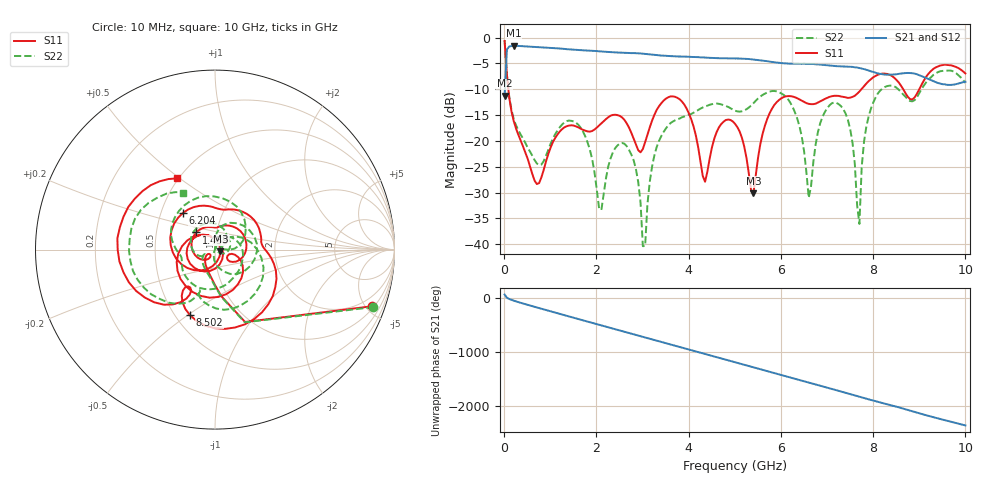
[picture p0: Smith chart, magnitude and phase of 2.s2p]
!Agilent Technologies,N5230C,MY49000813,A.09.42.22
!Agilent N5230C: A.09.42.22
!Date: Friday, August 21, 2026 19:33:07
!Correction: S11(Full 2 Port(1,2))
!S21(Full 2 Port(1,2))
!S12(Full 2 Port(1,2))
!S22(Full 2 Port(1,2))
!S2P File: Measurements: S11, S21, S12, S22:
# Hz S  dB  R 50
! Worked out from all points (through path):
!   201 points, 10 MHz to 10 GHz, reference 50 ohm
!   highest |S21| = -1.59 dB at 209.8 MHz (marker M1); lowest = -11.2 dB at 10 MHz (marker M2)
!   lowest |S11| = -30.1 dB at 5.405 GHz (marker M3), VSWR 1.06, Z = 53.1 - j0.895 ohm
!   |S11| at or under -10 dB: 91.73 MHz to 7.746 GHz (7.654 GHz wide, 195 % of centre); 8.653 GHz to 9 GHz (347.9 MHz wide, 3.94 % of centre)
!   |S22| runs from -40.4 to -0.5 dB; largest |S21 - S12| = 0.0031
!   S11 on the Smith chart (normalised r, x): 10 MHz: 1.16, -5.49; 1.459 GHz: 0.80, +0.16; 6.204 GHz: 0.65, +0.28; 8.502 GHz: 0.59, -0.51; 10 GHz: 0.49, +0.49
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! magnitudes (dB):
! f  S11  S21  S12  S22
! 10 MHz  -0.6  -11.2  -11.3  -0.5
! 209.8 MHz  -16.2  -1.6  -1.6  -15.8
! 709.3 MHz  -28.4  -1.8  -1.8  -24.4
! 1.459 GHz  -17.0  -2.3  -2.3  -16.1
! 1.708 GHz  -17.9  -2.5  -2.4  -18.2
! 2.108 GHz  -16.6  -2.7  -2.7  -33.4
! 2.707 GHz  -17.4  -3.0  -3.0  -21.7
! 3.007 GHz  -21.6  -3.1  -3.1  -40.4
! 3.357 GHz  -13.3  -3.4  -3.4  -20.0
! 3.906 GHz  -13.0  -3.7  -3.7  -15.3
! 4.356 GHz  -27.9  -3.9  -3.9  -13.3
! 5.005 GHz  -16.7  -4.0  -4.0  -14.2
! 5.405 GHz  -30.1  -4.2  -4.2  -12.7
! 6.204 GHz  -11.3  -5.0  -5.1  -12.6
! 6.603 GHz  -12.8  -5.1  -5.1  -31.0
! 6.703 GHz  -12.9  -5.1  -5.1  -24.1
! 7.353 GHz  -11.5  -5.6  -5.6  -13.9
! 7.702 GHz  -10.4  -5.9  -5.9  -36.1
! 7.852 GHz  -8.9  -6.2  -6.2  -17.3
! 8.352 GHz  -7.2  -7.2  -7.2  -9.3
! 8.502 GHz  -8.1  -7.1  -7.1  -9.7
! 10 GHz  -6.9  -8.5  -8.5  -8.8
